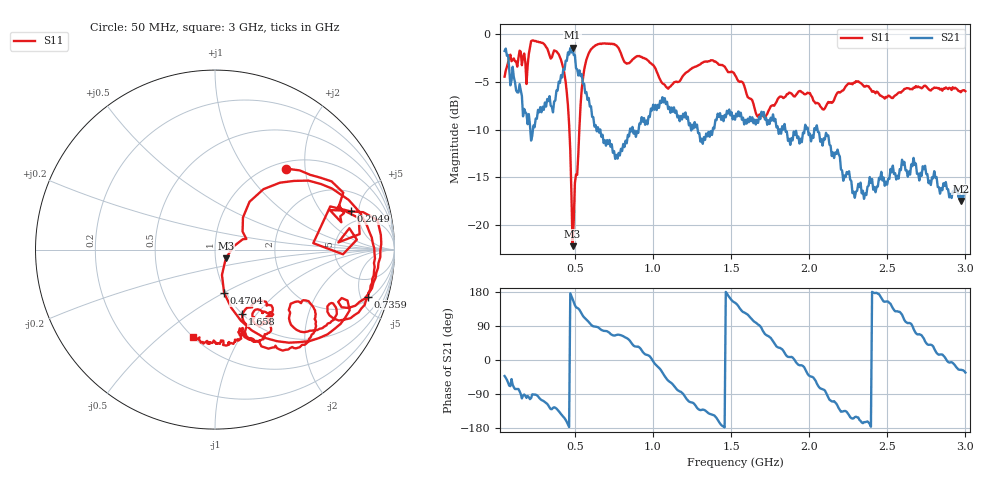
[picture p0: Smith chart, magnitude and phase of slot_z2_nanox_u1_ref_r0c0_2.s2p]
! nanovna_capture.py 2026-10-26T21:28:09+0900
! NanoVNA-F_V2 fw 0.6.0 SN 4A3639384505514B
! cal: load open short thru cal'ed  over 50000000-3000000000 Hz, 201 points
! points 401, avg 4
! slot line z=1.6, genuine Nano X, 0 deg, centred, placement 2
# HZ S RI R 50
! S12 and S22 are not measured (written as 0)
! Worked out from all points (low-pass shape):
!   401 points, 50 MHz to 3 GHz, reference 50 ohm
!   highest |S21| = -1.41 dB at 485.1 MHz (marker M1); lowest = -17.4 dB at 2.97 GHz (marker M2)
!   |S21| within 3 dB of the highest: start of sweep to 82.85 MHz; 419.7 MHz to 545.8 MHz (126.1 MHz wide, 26.1 % of centre) (the widest 2 of 4)
!   lowest |S11| = -22.2 dB at 485.1 MHz (marker M3), VSWR 1.17, Z = 56.1 - j5.56 ohm
!   |S11| at or under -10 dB: 464.6 MHz to 528.5 MHz (63.91 MHz wide, 12.9 % of centre)
!   S12 and S22 are empty: the file has one direction only
!   S11 on the Smith chart (normalised r, x): 50 MHz: 1.12, +1.58; 204.9 MHz: 3.66, +4.07; 470.4 MHz: 0.98, -0.50; 735.9 MHz: 2.25, -5.79; 1.658 GHz: 1.01, -0.84; 3 GHz: 0.50, -0.65
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5e7  0.3945 0.4516  0.6046 -0.5505  0 0  0 0
1.68e8  0.7485 0.119  -0.0232 -0.3709  0 0  0 0
2.04875e8  0.7567 0.2129  -0.0539 -0.3781  0 0  0 0
2.63875e8  0.9083 -0.102  -0.0407 -0.3998  0 0  0 0
4.04e8  0.578 -0.4932  -0.4191 -0.3652  0 0  0 0
4.4825e8  0.2043 -0.4499  -0.695 -0.2059  0 0  0 0
4.70375e8  0.0509 -0.242  -0.8429 0.059  0 0  0 0
4.85125e8  0.0601 -0.0492  -0.8038 0.2767  0 0  0 0
5.44125e8  0.3615 0.3727  -0.3204 0.5277  0 0  0 0
6.17875e8  0.8469 0.1334  0.00726 0.3677  0 0  0 0
7.35875e8  0.8525 -0.2624  0.105 0.2437  0 0  0 0
1.03825e9  0.4235 -0.4191  0.386 -0.1429  0 0  0 0
1.207875e9  0.5422 -0.3126  -0.0549 -0.3855  0 0  0 0
1.525e9  0.2761 -0.5448  -0.3129 0.172  0 0  0 0
1.65775e9  0.1531 -0.3565  -0.0512 0.3328  0 0  0 0
1.783125e9  0.302 -0.3088  0.2755 0.2319  0 0  0 0
2.019125e9  0.2222 -0.4128  0.2107 -0.2063  0 0  0 0
2.196125e9  0.2943 -0.3981  -0.1529 -0.1703  0 0  0 0
2.51325e9  0.1422 -0.4531  -0.1523 0.0857  0 0  0 0
2.668125e9  0.1129 -0.5132  0.0307 0.2231  0 0  0 0
2.9705e9  -0.0865 -0.489  0.1208 -0.0583  0 0  0 0
3e9  -0.1227 -0.4882  0.1225 -0.0799  0 0  0 0
